VERSION 5.8 ;
BUSBITCHARS "[]" ;
DIVIDERCHAR "/" ;
CLEARANCEMEASURE EUCLIDEAN ;
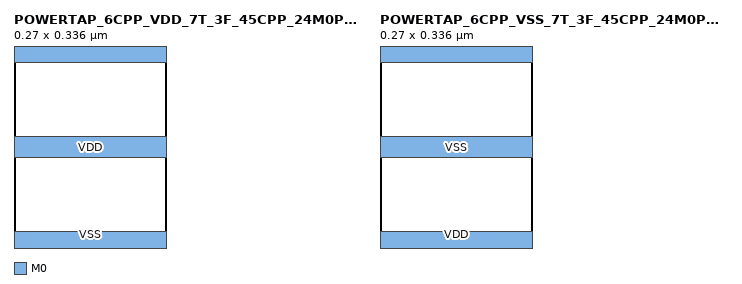
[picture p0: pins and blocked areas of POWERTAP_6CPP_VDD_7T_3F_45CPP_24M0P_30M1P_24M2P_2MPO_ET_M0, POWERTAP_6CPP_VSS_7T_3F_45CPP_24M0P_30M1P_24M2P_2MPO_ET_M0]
MACRO POWERTAP_6CPP_VDD_7T_3F_45CPP_24M0P_30M1P_24M2P_2MPO_ET_M0
  CLASS CORE ;
  ORIGIN 0 0 ;
  FOREIGN POWERTAP_6CPP_VDD_7T_3F_45CPP_24M0P_30M1P_24M2P_2MPO_ET_M0 ;
  SIZE 0.270 BY 0.336 ;
  SYMMETRY X Y ;
  SITE coresite ;
  PIN VSS
    DIRECTION INOUT ;
    USE GROUND ;
    SHAPE ABUTMENT ;
    PORT
      LAYER M0 ;
        RECT 0.000 -0.018 0.270 0.018 ;
        RECT 0.000 0.318 0.270 0.354 ;
    END
  END VSS
  PIN VDD
    DIRECTION INOUT ;
    USE POWER ;
    SHAPE ABUTMENT ;
    PORT
      LAYER M0 ;
        RECT 0.000 0.150 0.270 0.186 ;
    END
  END VDD
END POWERTAP_6CPP_VDD_7T_3F_45CPP_24M0P_30M1P_24M2P_2MPO_ET_M0

MACRO POWERTAP_6CPP_VSS_7T_3F_45CPP_24M0P_30M1P_24M2P_2MPO_ET_M0
  CLASS CORE ;
  ORIGIN 0 0 ;
  FOREIGN POWERTAP_6CPP_VSS_7T_3F_45CPP_24M0P_30M1P_24M2P_2MPO_ET_M0 ;
  SIZE 0.270 BY 0.336 ;
  SYMMETRY X Y ;
  SITE coresite ;
  PIN VDD
    DIRECTION INOUT ;
    USE POWER ;
    SHAPE ABUTMENT ;
    PORT
      LAYER M0 ;
        RECT 0.000 -0.018 0.270 0.018 ;
        RECT 0.000 0.318 0.270 0.354 ;
    END
  END VDD
  PIN VSS
    DIRECTION INOUT ;
    USE GROUND ;
    SHAPE ABUTMENT ;
    PORT
      LAYER M0 ;
        RECT 0.000 0.150 0.270 0.186 ;
    END
  END VSS
END POWERTAP_6CPP_VSS_7T_3F_45CPP_24M0P_30M1P_24M2P_2MPO_ET_M0
